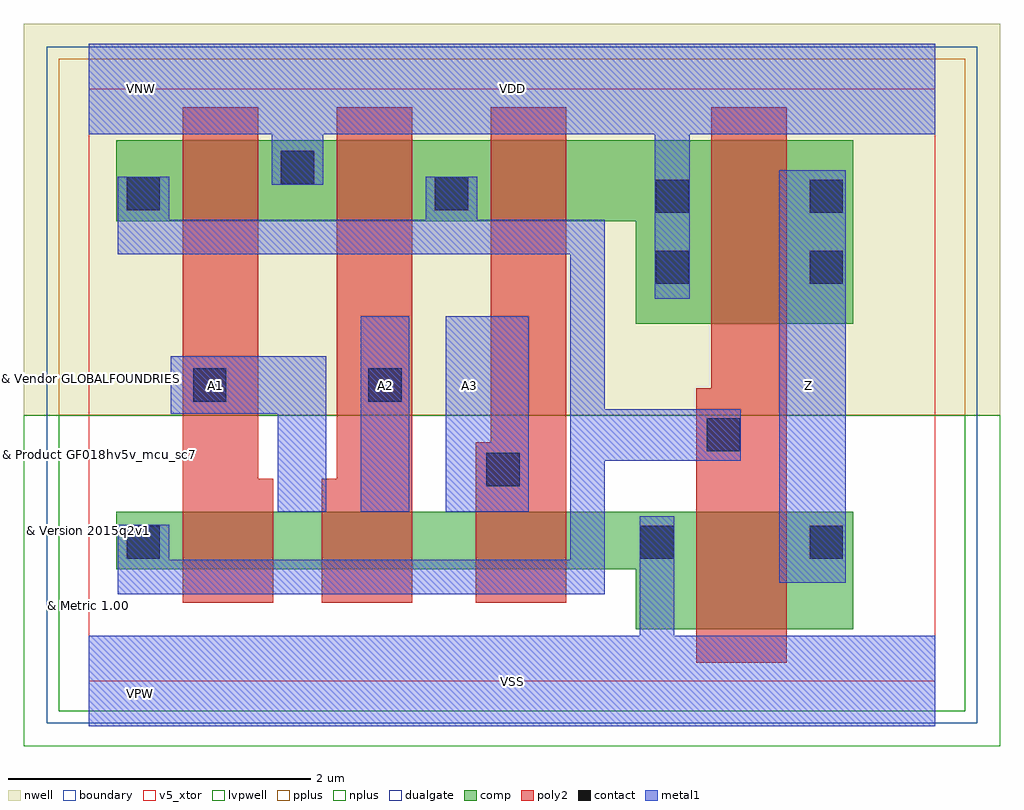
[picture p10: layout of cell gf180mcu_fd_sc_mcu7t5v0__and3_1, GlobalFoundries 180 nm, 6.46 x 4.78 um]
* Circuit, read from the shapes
.subckt gf180mcu_fd_sc_mcu7t5v0__and3_1 A1 A2 A3 VDD VNW VSS Z
XM1 n1 A1 n2 VSUBS nfet_05v0 w=0.38u l=0.6u
XM2 n3 A2 n1 VSUBS nfet_05v0 w=0.38u l=0.6u
XM3 VSS A3 n3 VSUBS nfet_05v0 w=0.38u l=0.6u
XM4 Z n2 VSS VSUBS nfet_05v0 w=0.775u l=0.6u
XM5 VDD A1 n2 VNW pfet_05v0 w=0.535u l=0.5u
XM6 n2 A2 VDD VNW pfet_05v0 w=0.535u l=0.5u
XM7 VDD A3 n2 VNW pfet_05v0 w=0.535u l=0.5u
XM8 Z n2 VDD VNW pfet_05v0 w=1.215u l=0.5u
.ends

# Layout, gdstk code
import gdstk
lib = gdstk.Library(unit=1e-6, precision=1e-09)
def R(c, l, rs):  # rectangles x0, y0, x1, y1
    for r in rs: c.add(gdstk.rectangle(r[:2], r[2:], *l))
def P(c, l, *ps):  # polygons
    for p in ps: c.add(gdstk.Polygon(p, *l))
boundary = (0, 0)
nwell = (21, 0)
comp = (22, 0)
poly2 = (30, 0)
pplus = (31, 0)
nplus = (32, 0)
contact = (33, 0)
metal1 = (34, 0)
dualgate = (55, 0)
v5_xtor = (112, 1)
lvpwell = (204, 0)

gf180mcu_fd_sc_mcu7t5v0_ = lib.new_cell('gf180mcu_fd_sc_mcu7t5v0__and3_1')
R(gf180mcu_fd_sc_mcu7t5v0_, boundary, [(0,0,5.6,3.92)])
R(gf180mcu_fd_sc_mcu7t5v0_, nwell, [(-0.43,1.76,6.03,4.35)])
P(gf180mcu_fd_sc_mcu7t5v0_, comp, [(3.62,0.345),(3.62,0.74),(0.18,0.74),(0.18,1.12),(5.06,1.12),(5.06,0.345)],
  [(3.62,2.365),(3.62,3.045),(0.18,3.045),(0.18,3.58),(5.06,3.58),(5.06,2.365)])
P(gf180mcu_fd_sc_mcu7t5v0_, poly2, [(0.62,0.52),(0.62,3.8),(1.12,3.8),(1.12,1.34),(1.22,1.34),(1.22,0.52)],
  [(1.54,0.52),(1.54,1.34),(1.64,1.34),(1.64,3.8),(2.14,3.8),(2.14,0.52)],
  [(2.56,0.52),(2.56,1.58),(2.66,1.58),(2.66,3.8),(3.16,3.8),(3.16,0.52)],
  [(4.02,0.12),(4.02,1.94),(4.12,1.94),(4.12,3.8),(4.62,3.8),(4.62,0.12)])
R(gf180mcu_fd_sc_mcu7t5v0_, pplus, [(-0.2,1.76,5.8,4.12)])
R(gf180mcu_fd_sc_mcu7t5v0_, nplus, [(-0.2,-0.2,5.8,1.76)])
R(gf180mcu_fd_sc_mcu7t5v0_, contact, [(0.25,0.81,0.47,1.03), (3.65,0.81,3.87,1.03), (4.77,0.81,4.99,1.03), (2.63,1.29,2.85,1.51), (4.09,1.52,4.31,1.74), (0.69,1.85,0.91,2.07), (1.85,1.85,2.07,2.07), (3.75,2.63,3.97,2.85), (4.77,2.63,4.99,2.85), (3.75,3.1,3.97,3.32), (4.77,3.1,4.99,3.32), (0.25,3.115,0.47,3.335), (2.29,3.115,2.51,3.335), (1.27,3.29,1.49,3.51)])
R(gf180mcu_fd_sc_mcu7t5v0_, metal1, [(4.57,0.65,5.01,3.38), (1.8,1.12,2.12,2.415), (2.36,1.12,2.91,2.415)])
P(gf180mcu_fd_sc_mcu7t5v0_, metal1, [(1.25,1.12),(1.25,1.77),(0.54,1.77),(0.54,2.15),(1.57,2.15),(1.57,1.12)],
  [(0.19,0.575),(0.19,1.035),(0.53,1.035),(0.53,0.805),(3.185,0.805),(3.185,2.825),(0.19,2.825),(0.19,3.34),(0.53,3.34),(0.53,3.055),(2.23,3.055),(2.23,3.34),(2.57,3.34),(2.57,3.055),(3.415,3.055),(3.415,1.8),(4.315,1.8),(4.315,1.46),(3.415,1.46),(3.415,0.575)],
  [(0,-0.3),(0,0.3),(3.645,0.3),(3.645,1.09),(3.875,1.09),(3.875,0.3),(5.6,0.3),(5.6,-0.3)],
  [(3.745,2.53),(3.745,3.62),(1.55,3.62),(1.55,3.285),(1.21,3.285),(1.21,3.62),(0,3.62),(0,4.22),(5.6,4.22),(5.6,3.62),(3.975,3.62),(3.975,2.53)])
R(gf180mcu_fd_sc_mcu7t5v0_, dualgate, [(-0.28,-0.28,5.88,4.2)])
R(gf180mcu_fd_sc_mcu7t5v0_, v5_xtor, [(0,0,5.6,3.92)])
R(gf180mcu_fd_sc_mcu7t5v0_, lvpwell, [(-0.43,-0.43,6.03,1.76)])
gf180mcu_fd_sc_mcu7t5v0_.add(gdstk.Label('A3', (2.52,1.96), layer=34, texttype=10))
gf180mcu_fd_sc_mcu7t5v0_.add(gdstk.Label('VDD', (2.8,3.92), layer=34, texttype=10))
gf180mcu_fd_sc_mcu7t5v0_.add(gdstk.Label('VSS', (2.8,0), layer=34, texttype=10))
gf180mcu_fd_sc_mcu7t5v0_.add(gdstk.Label('Z', (4.76,1.96), layer=34, texttype=10))
gf180mcu_fd_sc_mcu7t5v0_.add(gdstk.Label('A1', (0.84,1.96), layer=34, texttype=10))
gf180mcu_fd_sc_mcu7t5v0_.add(gdstk.Label('A2', (1.96,1.96), layer=34, texttype=10))
gf180mcu_fd_sc_mcu7t5v0_.add(gdstk.Label('& Vendor GLOBALFOUNDRIES', (0,2), layer=63, texttype=63))
gf180mcu_fd_sc_mcu7t5v0_.add(gdstk.Label('& Product GF018hv5v_mcu_sc7', (0,1.5), layer=63, texttype=63))
gf180mcu_fd_sc_mcu7t5v0_.add(gdstk.Label('& Version 2015q2v1', (0,1), layer=63, texttype=63))
gf180mcu_fd_sc_mcu7t5v0_.add(gdstk.Label('& Metric 1.00', (0,0.5), layer=63, texttype=63))
gf180mcu_fd_sc_mcu7t5v0_.add(gdstk.Label('VNW', (0.345,3.92), layer=21, texttype=10))
gf180mcu_fd_sc_mcu7t5v0_.add(gdstk.Label('VPW', (0.34,-0.085), layer=204, texttype=10))

lib.write_gds('gf180mcu_fd_sc_mcu7t5v0__and3_1.gds')
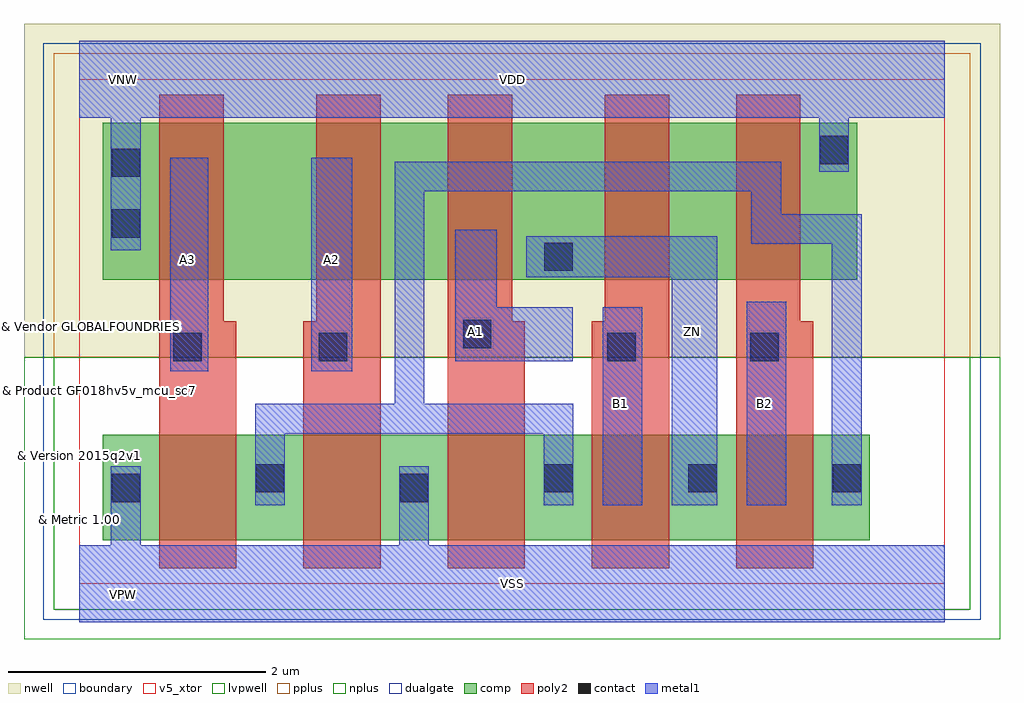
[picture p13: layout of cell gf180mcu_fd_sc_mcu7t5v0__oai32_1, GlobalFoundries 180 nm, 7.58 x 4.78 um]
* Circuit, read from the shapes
.subckt gf180mcu_fd_sc_mcu7t5v0__oai32_1 A1 A2 A3 B1 B2 VDD VNW VSS ZN
XM1 n1 A3 VSS VSUBS nfet_05v0 w=0.82u l=0.6u
XM2 VSS A2 n1 VSUBS nfet_05v0 w=0.82u l=0.6u
XM3 n1 A1 VSS VSUBS nfet_05v0 w=0.82u l=0.6u
XM4 ZN B1 n1 VSUBS nfet_05v0 w=0.82u l=0.6u
XM5 n1 B2 ZN VSUBS nfet_05v0 w=0.82u l=0.6u
XM6 n2 A3 VDD VNW pfet_05v0 w=1.22u l=0.5u
XM7 n3 A2 n2 VNW pfet_05v0 w=1.22u l=0.5u
XM8 ZN A1 n3 VNW pfet_05v0 w=1.22u l=0.5u
XM9 n4 B1 ZN VNW pfet_05v0 w=1.22u l=0.5u
XM10 VDD B2 n4 VNW pfet_05v0 w=1.22u l=0.5u
.ends

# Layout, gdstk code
import gdstk
lib = gdstk.Library(unit=1e-6, precision=1e-09)
def R(c, l, rs):  # rectangles x0, y0, x1, y1
    for r in rs: c.add(gdstk.rectangle(r[:2], r[2:], *l))
def A(c, l, x, y, w, h, nx, ny, dx, dy):  # array of equal rectangles
    R(c, l, [(x+i*dx, y+j*dy, x+i*dx+w, y+j*dy+h) for i in range(nx) for j in range(ny)])
def P(c, l, *ps):  # polygons
    for p in ps: c.add(gdstk.Polygon(p, *l))
boundary = (0, 0)
nwell = (21, 0)
comp = (22, 0)
poly2 = (30, 0)
pplus = (31, 0)
nplus = (32, 0)
contact = (33, 0)
metal1 = (34, 0)
dualgate = (55, 0)
v5_xtor = (112, 1)
lvpwell = (204, 0)

gf180mcu_fd_sc_mcu7t5v0_ = lib.new_cell('gf180mcu_fd_sc_mcu7t5v0__oai32_1')
R(gf180mcu_fd_sc_mcu7t5v0_, boundary, [(0,0,6.72,3.92)])
R(gf180mcu_fd_sc_mcu7t5v0_, nwell, [(-0.43,1.76,7.15,4.35)])
R(gf180mcu_fd_sc_mcu7t5v0_, comp, [(0.18,0.34,6.14,1.16), (0.18,2.36,6.04,3.58)])
P(gf180mcu_fd_sc_mcu7t5v0_, poly2, [(0.62,0.12),(0.62,3.8),(1.12,3.8),(1.12,2.04),(1.22,2.04),(1.22,0.12)],
  [(1.74,0.12),(1.74,2.04),(1.84,2.04),(1.84,3.8),(2.34,3.8),(2.34,0.12)],
  [(2.86,0.12),(2.86,3.8),(3.36,3.8),(3.36,2.04),(3.46,2.04),(3.46,0.12)],
  [(3.98,0.12),(3.98,2.04),(4.08,2.04),(4.08,3.8),(4.58,3.8),(4.58,0.12)],
  [(5.1,0.12),(5.1,3.8),(5.6,3.8),(5.6,2.04),(5.7,2.04),(5.7,0.12)])
R(gf180mcu_fd_sc_mcu7t5v0_, pplus, [(-0.2,1.76,6.92,4.12)])
R(gf180mcu_fd_sc_mcu7t5v0_, nplus, [(-0.2,-0.2,6.92,1.76)])
A(gf180mcu_fd_sc_mcu7t5v0_, contact, 3.61, 0.71, 0.22, 0.22, 3, 1, 1.12, 0)
R(gf180mcu_fd_sc_mcu7t5v0_, contact, [(0.25,0.635,0.47,0.855), (2.49,0.635,2.71,0.855), (1.37,0.71,1.59,0.93), (0.73,1.73,0.95,1.95), (1.86,1.73,2.08,1.95), (4.1,1.73,4.32,1.95), (5.21,1.73,5.43,1.95), (2.98,1.83,3.2,2.05), (3.61,2.43,3.83,2.65), (0.25,2.69,0.47,2.91), (0.25,3.16,0.47,3.38), (5.75,3.26,5.97,3.48)])
R(gf180mcu_fd_sc_mcu7t5v0_, metal1, [(4.065,0.61,4.37,2.15), (5.185,0.61,5.49,2.19), (0.705,1.65,1,3.31), (1.8,1.65,2.12,3.31)])
P(gf180mcu_fd_sc_mcu7t5v0_, metal1, [(2.92,1.73),(2.92,2.75),(3.24,2.75),(3.24,2.15),(3.83,2.15),(3.83,1.73)],
  [(4.6,0.61),(4.6,2.38),(3.47,2.38),(3.47,2.7),(4.955,2.7),(4.955,0.61)],
  [(1.365,0.61),(1.365,1.4),(2.45,1.4),(2.45,3.28),(5.45,3.28),(5.45,2.87),(6.075,2.87),(6.075,0.61),(5.845,0.61),(5.845,2.64),(5.22,2.64),(5.22,3.05),(2.68,3.05),(2.68,1.4),(3.835,1.4),(3.835,0.61),(3.605,0.61),(3.605,1.165),(1.595,1.165),(1.595,0.61)],
  [(0,-0.3),(0,0.3),(0.245,0.3),(0.245,0.915),(0.475,0.915),(0.475,0.3),(2.485,0.3),(2.485,0.915),(2.715,0.915),(2.715,0.3),(6.72,0.3),(6.72,-0.3)],
  [(0.245,2.59),(0.245,3.62),(0,3.62),(0,4.22),(6.72,4.22),(6.72,3.62),(5.975,3.62),(5.975,3.2),(5.745,3.2),(5.745,3.62),(0.475,3.62),(0.475,2.59)])
R(gf180mcu_fd_sc_mcu7t5v0_, dualgate, [(-0.28,-0.28,7,4.2)])
R(gf180mcu_fd_sc_mcu7t5v0_, v5_xtor, [(0,0,6.72,3.92)])
R(gf180mcu_fd_sc_mcu7t5v0_, lvpwell, [(-0.43,-0.43,7.15,1.76)])
gf180mcu_fd_sc_mcu7t5v0_.add(gdstk.Label('A3', (0.84,2.52), layer=34, texttype=10))
gf180mcu_fd_sc_mcu7t5v0_.add(gdstk.Label('B1', (4.2,1.4), layer=34, texttype=10))
gf180mcu_fd_sc_mcu7t5v0_.add(gdstk.Label('B2', (5.32,1.4), layer=34, texttype=10))
gf180mcu_fd_sc_mcu7t5v0_.add(gdstk.Label('VDD', (3.36,3.92), layer=34, texttype=10))
gf180mcu_fd_sc_mcu7t5v0_.add(gdstk.Label('VSS', (3.36,0), layer=34, texttype=10))
gf180mcu_fd_sc_mcu7t5v0_.add(gdstk.Label('ZN', (4.76,1.96), layer=34, texttype=10))
gf180mcu_fd_sc_mcu7t5v0_.add(gdstk.Label('A1', (3.08,1.96), layer=34, texttype=10))
gf180mcu_fd_sc_mcu7t5v0_.add(gdstk.Label('A2', (1.96,2.52), layer=34, texttype=10))
gf180mcu_fd_sc_mcu7t5v0_.add(gdstk.Label('& Vendor GLOBALFOUNDRIES', (0,2), layer=63, texttype=63))
gf180mcu_fd_sc_mcu7t5v0_.add(gdstk.Label('& Product GF018hv5v_mcu_sc7', (0,1.5), layer=63, texttype=63))
gf180mcu_fd_sc_mcu7t5v0_.add(gdstk.Label('& Version 2015q2v1', (0,1), layer=63, texttype=63))
gf180mcu_fd_sc_mcu7t5v0_.add(gdstk.Label('& Metric 1.00', (0,0.5), layer=63, texttype=63))
gf180mcu_fd_sc_mcu7t5v0_.add(gdstk.Label('VNW', (0.345,3.92), layer=21, texttype=10))
gf180mcu_fd_sc_mcu7t5v0_.add(gdstk.Label('VPW', (0.34,-0.085), layer=204, texttype=10))

lib.write_gds('gf180mcu_fd_sc_mcu7t5v0__oai32_1.gds')
